VERSION 5.8 ;
BUSBITCHARS "[]" ;
DIVIDERCHAR "/" ;

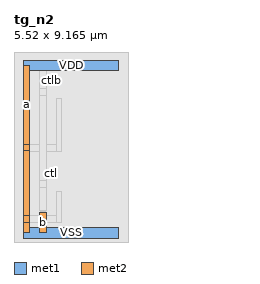
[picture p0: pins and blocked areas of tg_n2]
MACRO tg_n2
  CLASS BLOCK ;
  FOREIGN tg_n2 0 0 ;
  ORIGIN 0 0 ;
  SIZE 5.520 BY 9.165 ;
  SYMMETRY X Y ;
  PIN VDD
    DIRECTION INOUT ;
    USE POWER ;
    PORT
      LAYER met1 ;
        RECT 0.460 8.255 5.060 8.755 ;
    END
  END VDD
  PIN VSS
    DIRECTION INOUT ;
    USE GROUND ;
    PORT
      LAYER met1 ;
        RECT 0.460 0.185 5.060 0.685 ;
    END
  END VSS
  PIN a
    DIRECTION INOUT ;
    USE SIGNAL ;
    PORT
      LAYER met2 ;
        RECT 0.455 4.720 0.755 8.505 ;
        RECT 0.440 4.390 0.770 4.720 ;
        RECT 0.455 1.260 0.755 4.390 ;
        RECT 0.440 0.930 0.770 1.260 ;
        RECT 0.455 0.435 0.755 0.930 ;
    END
  END a
  PIN b
    DIRECTION INOUT ;
    USE SIGNAL ;
    PORT
      LAYER met2 ;
        RECT 1.245 0.435 1.545 1.400 ;
    END
  END b
  PIN ctl
    DIRECTION INPUT ;
    USE SIGNAL ;
    PORT
      LAYER met1 ;
        RECT 1.620 3.145 1.960 3.485 ;
    END
  END ctl
  PIN ctlb
    DIRECTION INPUT ;
    USE SIGNAL ;
    PORT
      LAYER met1 ;
        RECT 1.620 7.605 1.960 7.945 ;
    END
  END ctlb
  OBS
    LAYER li1 ;
      RECT 0.000 0.000 5.520 9.165 ;
    LAYER met1 ;
      RECT 0.490 1.265 0.720 2.455 ;
      RECT 2.070 0.925 2.300 2.455 ;
      RECT 0.440 0.930 0.490 1.260 ;
      RECT 0.490 0.925 2.070 1.265 ;
      RECT 1.230 2.630 1.280 2.960 ;
      RECT 1.280 1.455 1.510 2.625 ;
      RECT 1.280 2.625 1.560 2.965 ;
      RECT 0.490 4.725 0.720 6.915 ;
      RECT 2.070 4.385 2.300 6.915 ;
      RECT 0.440 4.390 0.490 4.720 ;
      RECT 0.490 4.385 2.070 4.725 ;
      RECT 1.230 7.090 1.280 7.420 ;
      RECT 1.280 4.915 1.510 7.085 ;
      RECT 1.280 7.085 1.560 7.425 ;
    LAYER met2 ;
      RECT 1.245 7.420 1.545 8.505 ;
      RECT 1.230 7.090 1.560 7.420 ;
      RECT 1.245 2.960 1.545 7.090 ;
      RECT 1.230 2.630 1.560 2.960 ;
      RECT 1.245 1.540 1.545 2.630 ;
  END
END tg_n2

END LIBRARY
